VERSION 5.8 ;
BUSBITCHARS "[]" ;
DIVIDERCHAR "/" ;
UNITS
    DATABASE MICRONS 1000 ;
END UNITS

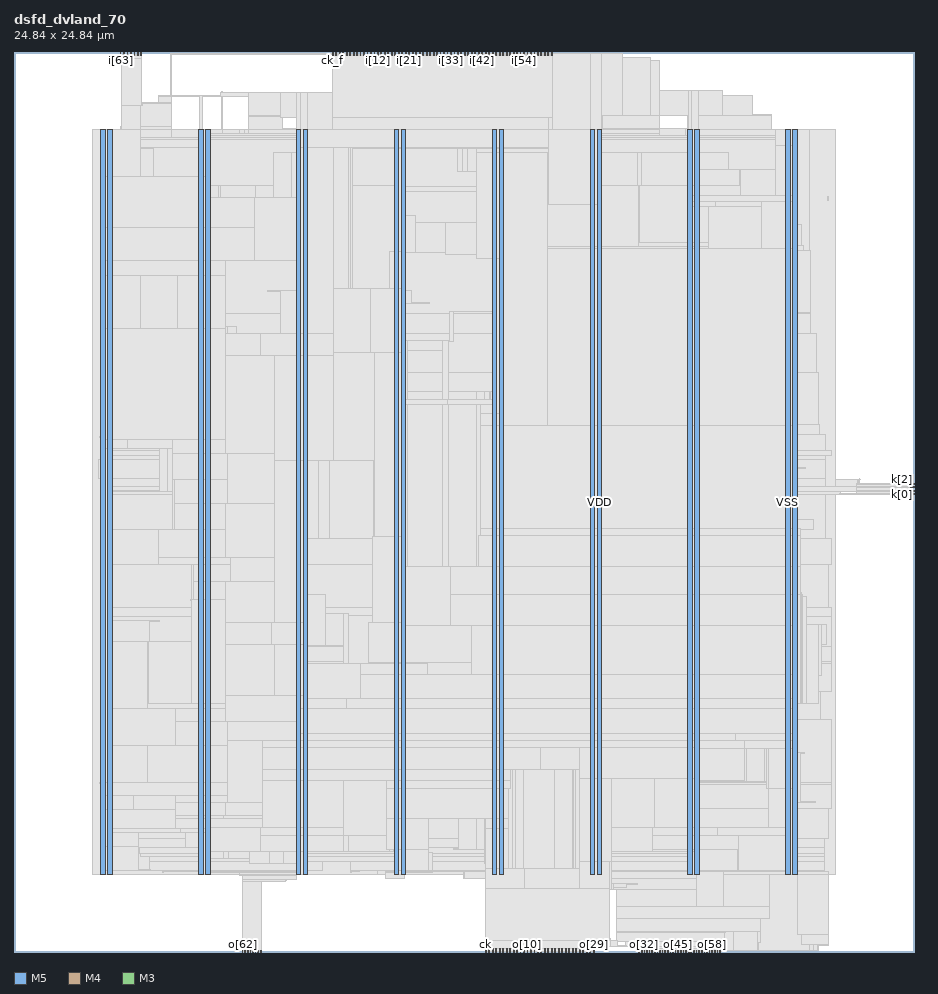
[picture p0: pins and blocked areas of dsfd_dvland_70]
MACRO dsfd_dvland_70
  FOREIGN dsfd_dvland_70 0 0 ;
  CLASS BLOCK ;
  SIZE 24.84 BY 24.84 ;
  PIN ck
    DIRECTION INPUT ;
    USE SIGNAL ;
    PORT
      LAYER M5 ;
        RECT  13.008 0 13.032 0.084 ;
    END
  END ck
  PIN ck_f
    DIRECTION INPUT ;
    USE SIGNAL ;
    PORT
      LAYER M5 ;
        RECT  8.784 24.756 8.808 24.84 ;
    END
  END ck_f
  PIN fault
    DIRECTION OUTPUT ;
    USE SIGNAL ;
    PORT
      LAYER M5 ;
        RECT  13.104 0 13.128 0.084 ;
    END
  END fault
  PIN i[0]
    DIRECTION INPUT ;
    USE SIGNAL ;
    PORT
      LAYER M5 ;
        RECT  8.88 24.756 8.904 24.84 ;
    END
  END i[0]
  PIN i[10]
    DIRECTION INPUT ;
    USE SIGNAL ;
    PORT
      LAYER M5 ;
        RECT  9.84 24.756 9.864 24.84 ;
    END
  END i[10]
  PIN i[11]
    DIRECTION INPUT ;
    USE SIGNAL ;
    PORT
      LAYER M5 ;
        RECT  9.936 24.756 9.96 24.84 ;
    END
  END i[11]
  PIN i[12]
    DIRECTION INPUT ;
    USE SIGNAL ;
    PORT
      LAYER M5 ;
        RECT  10.032 24.756 10.056 24.84 ;
    END
  END i[12]
  PIN i[13]
    DIRECTION INPUT ;
    USE SIGNAL ;
    PORT
      LAYER M5 ;
        RECT  10.128 24.756 10.152 24.84 ;
    END
  END i[13]
  PIN i[14]
    DIRECTION INPUT ;
    USE SIGNAL ;
    PORT
      LAYER M5 ;
        RECT  10.224 24.756 10.248 24.84 ;
    END
  END i[14]
  PIN i[15]
    DIRECTION INPUT ;
    USE SIGNAL ;
    PORT
      LAYER M5 ;
        RECT  10.32 24.756 10.344 24.84 ;
    END
  END i[15]
  PIN i[16]
    DIRECTION INPUT ;
    USE SIGNAL ;
    PORT
      LAYER M5 ;
        RECT  10.416 24.756 10.44 24.84 ;
    END
  END i[16]
  PIN i[17]
    DIRECTION INPUT ;
    USE SIGNAL ;
    PORT
      LAYER M5 ;
        RECT  10.512 24.756 10.536 24.84 ;
    END
  END i[17]
  PIN i[18]
    DIRECTION INPUT ;
    USE SIGNAL ;
    PORT
      LAYER M5 ;
        RECT  10.608 24.756 10.632 24.84 ;
    END
  END i[18]
  PIN i[19]
    DIRECTION INPUT ;
    USE SIGNAL ;
    PORT
      LAYER M5 ;
        RECT  10.704 24.756 10.728 24.84 ;
    END
  END i[19]
  PIN i[1]
    DIRECTION INPUT ;
    USE SIGNAL ;
    PORT
      LAYER M5 ;
        RECT  8.976 24.756 9 24.84 ;
    END
  END i[1]
  PIN i[20]
    DIRECTION INPUT ;
    USE SIGNAL ;
    PORT
      LAYER M5 ;
        RECT  10.8 24.756 10.824 24.84 ;
    END
  END i[20]
  PIN i[21]
    DIRECTION INPUT ;
    USE SIGNAL ;
    PORT
      LAYER M5 ;
        RECT  10.896 24.756 10.92 24.84 ;
    END
  END i[21]
  PIN i[22]
    DIRECTION INPUT ;
    USE SIGNAL ;
    PORT
      LAYER M5 ;
        RECT  10.992 24.756 11.016 24.84 ;
    END
  END i[22]
  PIN i[23]
    DIRECTION INPUT ;
    USE SIGNAL ;
    PORT
      LAYER M5 ;
        RECT  11.088 24.756 11.112 24.84 ;
    END
  END i[23]
  PIN i[24]
    DIRECTION INPUT ;
    USE SIGNAL ;
    PORT
      LAYER M5 ;
        RECT  11.184 24.756 11.208 24.84 ;
    END
  END i[24]
  PIN i[25]
    DIRECTION INPUT ;
    USE SIGNAL ;
    PORT
      LAYER M5 ;
        RECT  11.28 24.756 11.304 24.84 ;
    END
  END i[25]
  PIN i[26]
    DIRECTION INPUT ;
    USE SIGNAL ;
    PORT
      LAYER M5 ;
        RECT  11.376 24.756 11.4 24.84 ;
    END
  END i[26]
  PIN i[27]
    DIRECTION INPUT ;
    USE SIGNAL ;
    PORT
      LAYER M5 ;
        RECT  11.472 24.756 11.496 24.84 ;
    END
  END i[27]
  PIN i[28]
    DIRECTION INPUT ;
    USE SIGNAL ;
    PORT
      LAYER M5 ;
        RECT  11.568 24.756 11.592 24.84 ;
    END
  END i[28]
  PIN i[29]
    DIRECTION INPUT ;
    USE SIGNAL ;
    PORT
      LAYER M5 ;
        RECT  11.664 24.756 11.688 24.84 ;
    END
  END i[29]
  PIN i[2]
    DIRECTION INPUT ;
    USE SIGNAL ;
    PORT
      LAYER M5 ;
        RECT  9.072 24.756 9.096 24.84 ;
    END
  END i[2]
  PIN i[30]
    DIRECTION INPUT ;
    USE SIGNAL ;
    PORT
      LAYER M5 ;
        RECT  11.76 24.756 11.784 24.84 ;
    END
  END i[30]
  PIN i[31]
    DIRECTION INPUT ;
    USE SIGNAL ;
    PORT
      LAYER M5 ;
        RECT  11.856 24.756 11.88 24.84 ;
    END
  END i[31]
  PIN i[32]
    DIRECTION INPUT ;
    USE SIGNAL ;
    PORT
      LAYER M5 ;
        RECT  11.952 24.756 11.976 24.84 ;
    END
  END i[32]
  PIN i[33]
    DIRECTION INPUT ;
    USE SIGNAL ;
    PORT
      LAYER M5 ;
        RECT  12.048 24.756 12.072 24.84 ;
    END
  END i[33]
  PIN i[34]
    DIRECTION INPUT ;
    USE SIGNAL ;
    PORT
      LAYER M5 ;
        RECT  12.144 24.756 12.168 24.84 ;
    END
  END i[34]
  PIN i[35]
    DIRECTION INPUT ;
    USE SIGNAL ;
    PORT
      LAYER M5 ;
        RECT  12.24 24.756 12.264 24.84 ;
    END
  END i[35]
  PIN i[36]
    DIRECTION INPUT ;
    USE SIGNAL ;
    PORT
      LAYER M5 ;
        RECT  12.336 24.756 12.36 24.84 ;
    END
  END i[36]
  PIN i[37]
    DIRECTION INPUT ;
    USE SIGNAL ;
    PORT
      LAYER M5 ;
        RECT  12.432 24.756 12.456 24.84 ;
    END
  END i[37]
  PIN i[38]
    DIRECTION INPUT ;
    USE SIGNAL ;
    PORT
      LAYER M5 ;
        RECT  12.528 24.756 12.552 24.84 ;
    END
  END i[38]
  PIN i[39]
    DIRECTION INPUT ;
    USE SIGNAL ;
    PORT
      LAYER M5 ;
        RECT  12.624 24.756 12.648 24.84 ;
    END
  END i[39]
  PIN i[3]
    DIRECTION INPUT ;
    USE SIGNAL ;
    PORT
      LAYER M5 ;
        RECT  9.168 24.756 9.192 24.84 ;
    END
  END i[3]
  PIN i[40]
    DIRECTION INPUT ;
    USE SIGNAL ;
    PORT
      LAYER M5 ;
        RECT  12.72 24.756 12.744 24.84 ;
    END
  END i[40]
  PIN i[41]
    DIRECTION INPUT ;
    USE SIGNAL ;
    PORT
      LAYER M5 ;
        RECT  12.816 24.756 12.84 24.84 ;
    END
  END i[41]
  PIN i[42]
    DIRECTION INPUT ;
    USE SIGNAL ;
    PORT
      LAYER M5 ;
        RECT  12.912 24.756 12.936 24.84 ;
    END
  END i[42]
  PIN i[43]
    DIRECTION INPUT ;
    USE SIGNAL ;
    PORT
      LAYER M5 ;
        RECT  13.008 24.756 13.032 24.84 ;
    END
  END i[43]
  PIN i[44]
    DIRECTION INPUT ;
    USE SIGNAL ;
    PORT
      LAYER M5 ;
        RECT  13.104 24.756 13.128 24.84 ;
    END
  END i[44]
  PIN i[45]
    DIRECTION INPUT ;
    USE SIGNAL ;
    PORT
      LAYER M5 ;
        RECT  13.2 24.756 13.224 24.84 ;
    END
  END i[45]
  PIN i[46]
    DIRECTION INPUT ;
    USE SIGNAL ;
    PORT
      LAYER M5 ;
        RECT  13.296 24.756 13.32 24.84 ;
    END
  END i[46]
  PIN i[47]
    DIRECTION INPUT ;
    USE SIGNAL ;
    PORT
      LAYER M5 ;
        RECT  13.392 24.756 13.416 24.84 ;
    END
  END i[47]
  PIN i[48]
    DIRECTION INPUT ;
    USE SIGNAL ;
    PORT
      LAYER M5 ;
        RECT  13.488 24.756 13.512 24.84 ;
    END
  END i[48]
  PIN i[49]
    DIRECTION INPUT ;
    USE SIGNAL ;
    PORT
      LAYER M5 ;
        RECT  13.584 24.756 13.608 24.84 ;
    END
  END i[49]
  PIN i[4]
    DIRECTION INPUT ;
    USE SIGNAL ;
    PORT
      LAYER M5 ;
        RECT  9.264 24.756 9.288 24.84 ;
    END
  END i[4]
  PIN i[50]
    DIRECTION INPUT ;
    USE SIGNAL ;
    PORT
      LAYER M5 ;
        RECT  13.68 24.756 13.704 24.84 ;
    END
  END i[50]
  PIN i[51]
    DIRECTION INPUT ;
    USE SIGNAL ;
    PORT
      LAYER M5 ;
        RECT  13.776 24.756 13.8 24.84 ;
    END
  END i[51]
  PIN i[52]
    DIRECTION INPUT ;
    USE SIGNAL ;
    PORT
      LAYER M5 ;
        RECT  13.872 24.756 13.896 24.84 ;
    END
  END i[52]
  PIN i[53]
    DIRECTION INPUT ;
    USE SIGNAL ;
    PORT
      LAYER M5 ;
        RECT  13.968 24.756 13.992 24.84 ;
    END
  END i[53]
  PIN i[54]
    DIRECTION INPUT ;
    USE SIGNAL ;
    PORT
      LAYER M5 ;
        RECT  14.064 24.756 14.088 24.84 ;
    END
  END i[54]
  PIN i[55]
    DIRECTION INPUT ;
    USE SIGNAL ;
    PORT
      LAYER M5 ;
        RECT  14.16 24.756 14.184 24.84 ;
    END
  END i[55]
  PIN i[56]
    DIRECTION INPUT ;
    USE SIGNAL ;
    PORT
      LAYER M5 ;
        RECT  14.256 24.756 14.28 24.84 ;
    END
  END i[56]
  PIN i[57]
    DIRECTION INPUT ;
    USE SIGNAL ;
    PORT
      LAYER M5 ;
        RECT  14.352 24.756 14.376 24.84 ;
    END
  END i[57]
  PIN i[58]
    DIRECTION INPUT ;
    USE SIGNAL ;
    PORT
      LAYER M5 ;
        RECT  14.448 24.756 14.472 24.84 ;
    END
  END i[58]
  PIN i[59]
    DIRECTION INPUT ;
    USE SIGNAL ;
    PORT
      LAYER M5 ;
        RECT  14.544 24.756 14.568 24.84 ;
    END
  END i[59]
  PIN i[5]
    DIRECTION INPUT ;
    USE SIGNAL ;
    PORT
      LAYER M5 ;
        RECT  9.36 24.756 9.384 24.84 ;
    END
  END i[5]
  PIN i[60]
    DIRECTION INPUT ;
    USE SIGNAL ;
    PORT
      LAYER M5 ;
        RECT  14.64 24.756 14.664 24.84 ;
    END
  END i[60]
  PIN i[61]
    DIRECTION INPUT ;
    USE SIGNAL ;
    PORT
      LAYER M5 ;
        RECT  14.736 24.756 14.76 24.84 ;
    END
  END i[61]
  PIN i[62]
    DIRECTION INPUT ;
    USE SIGNAL ;
    PORT
      LAYER M5 ;
        RECT  14.832 24.756 14.856 24.84 ;
    END
  END i[62]
  PIN i[63]
    DIRECTION INPUT ;
    USE SIGNAL ;
    PORT
      LAYER M5 ;
        RECT  2.928 24.756 2.952 24.84 ;
    END
  END i[63]
  PIN i[64]
    DIRECTION INPUT ;
    USE SIGNAL ;
    PORT
      LAYER M5 ;
        RECT  3.024 24.756 3.048 24.84 ;
    END
  END i[64]
  PIN i[65]
    DIRECTION INPUT ;
    USE SIGNAL ;
    PORT
      LAYER M5 ;
        RECT  3.12 24.756 3.144 24.84 ;
    END
  END i[65]
  PIN i[66]
    DIRECTION INPUT ;
    USE SIGNAL ;
    PORT
      LAYER M5 ;
        RECT  3.216 24.756 3.24 24.84 ;
    END
  END i[66]
  PIN i[67]
    DIRECTION INPUT ;
    USE SIGNAL ;
    PORT
      LAYER M5 ;
        RECT  3.312 24.756 3.336 24.84 ;
    END
  END i[67]
  PIN i[68]
    DIRECTION INPUT ;
    USE SIGNAL ;
    PORT
      LAYER M5 ;
        RECT  3.408 24.756 3.432 24.84 ;
    END
  END i[68]
  PIN i[69]
    DIRECTION INPUT ;
    USE SIGNAL ;
    PORT
      LAYER M5 ;
        RECT  3.504 24.756 3.528 24.84 ;
    END
  END i[69]
  PIN i[6]
    DIRECTION INPUT ;
    USE SIGNAL ;
    PORT
      LAYER M5 ;
        RECT  9.456 24.756 9.48 24.84 ;
    END
  END i[6]
  PIN i[7]
    DIRECTION INPUT ;
    USE SIGNAL ;
    PORT
      LAYER M5 ;
        RECT  9.552 24.756 9.576 24.84 ;
    END
  END i[7]
  PIN i[8]
    DIRECTION INPUT ;
    USE SIGNAL ;
    PORT
      LAYER M5 ;
        RECT  9.648 24.756 9.672 24.84 ;
    END
  END i[8]
  PIN i[9]
    DIRECTION INPUT ;
    USE SIGNAL ;
    PORT
      LAYER M5 ;
        RECT  9.744 24.756 9.768 24.84 ;
    END
  END i[9]
  PIN k[0]
    DIRECTION INPUT ;
    USE SIGNAL ;
    PORT
      LAYER M4 ;
        RECT  24.756 12.624 24.84 12.648 ;
    END
  END k[0]
  PIN k[1]
    DIRECTION INPUT ;
    USE SIGNAL ;
    PORT
      LAYER M4 ;
        RECT  24.756 12.72 24.84 12.744 ;
    END
  END k[1]
  PIN k[2]
    DIRECTION INPUT ;
    USE SIGNAL ;
    PORT
      LAYER M4 ;
        RECT  24.756 12.816 24.84 12.84 ;
    END
  END k[2]
  PIN o[0]
    DIRECTION OUTPUT ;
    USE SIGNAL ;
    PORT
      LAYER M5 ;
        RECT  13.2 0 13.224 0.084 ;
    END
  END o[0]
  PIN o[10]
    DIRECTION OUTPUT ;
    USE SIGNAL ;
    PORT
      LAYER M5 ;
        RECT  14.16 0 14.184 0.084 ;
    END
  END o[10]
  PIN o[11]
    DIRECTION OUTPUT ;
    USE SIGNAL ;
    PORT
      LAYER M5 ;
        RECT  14.256 0 14.28 0.084 ;
    END
  END o[11]
  PIN o[12]
    DIRECTION OUTPUT ;
    USE SIGNAL ;
    PORT
      LAYER M5 ;
        RECT  14.352 0 14.376 0.084 ;
    END
  END o[12]
  PIN o[13]
    DIRECTION OUTPUT ;
    USE SIGNAL ;
    PORT
      LAYER M5 ;
        RECT  14.448 0 14.472 0.084 ;
    END
  END o[13]
  PIN o[14]
    DIRECTION OUTPUT ;
    USE SIGNAL ;
    PORT
      LAYER M5 ;
        RECT  14.544 0 14.568 0.084 ;
    END
  END o[14]
  PIN o[15]
    DIRECTION OUTPUT ;
    USE SIGNAL ;
    PORT
      LAYER M5 ;
        RECT  14.64 0 14.664 0.084 ;
    END
  END o[15]
  PIN o[16]
    DIRECTION OUTPUT ;
    USE SIGNAL ;
    PORT
      LAYER M5 ;
        RECT  14.736 0 14.76 0.084 ;
    END
  END o[16]
  PIN o[17]
    DIRECTION OUTPUT ;
    USE SIGNAL ;
    PORT
      LAYER M5 ;
        RECT  14.832 0 14.856 0.084 ;
    END
  END o[17]
  PIN o[18]
    DIRECTION OUTPUT ;
    USE SIGNAL ;
    PORT
      LAYER M5 ;
        RECT  14.928 0 14.952 0.084 ;
    END
  END o[18]
  PIN o[19]
    DIRECTION OUTPUT ;
    USE SIGNAL ;
    PORT
      LAYER M5 ;
        RECT  15.024 0 15.048 0.084 ;
    END
  END o[19]
  PIN o[1]
    DIRECTION OUTPUT ;
    USE SIGNAL ;
    PORT
      LAYER M5 ;
        RECT  13.296 0 13.32 0.084 ;
    END
  END o[1]
  PIN o[20]
    DIRECTION OUTPUT ;
    USE SIGNAL ;
    PORT
      LAYER M5 ;
        RECT  15.12 0 15.144 0.084 ;
    END
  END o[20]
  PIN o[21]
    DIRECTION OUTPUT ;
    USE SIGNAL ;
    PORT
      LAYER M5 ;
        RECT  15.216 0 15.24 0.084 ;
    END
  END o[21]
  PIN o[22]
    DIRECTION OUTPUT ;
    USE SIGNAL ;
    PORT
      LAYER M5 ;
        RECT  15.312 0 15.336 0.084 ;
    END
  END o[22]
  PIN o[23]
    DIRECTION OUTPUT ;
    USE SIGNAL ;
    PORT
      LAYER M5 ;
        RECT  15.408 0 15.432 0.084 ;
    END
  END o[23]
  PIN o[24]
    DIRECTION OUTPUT ;
    USE SIGNAL ;
    PORT
      LAYER M5 ;
        RECT  15.504 0 15.528 0.084 ;
    END
  END o[24]
  PIN o[25]
    DIRECTION OUTPUT ;
    USE SIGNAL ;
    PORT
      LAYER M5 ;
        RECT  15.6 0 15.624 0.084 ;
    END
  END o[25]
  PIN o[26]
    DIRECTION OUTPUT ;
    USE SIGNAL ;
    PORT
      LAYER M5 ;
        RECT  15.696 0 15.72 0.084 ;
    END
  END o[26]
  PIN o[27]
    DIRECTION OUTPUT ;
    USE SIGNAL ;
    PORT
      LAYER M5 ;
        RECT  15.792 0 15.816 0.084 ;
    END
  END o[27]
  PIN o[28]
    DIRECTION OUTPUT ;
    USE SIGNAL ;
    PORT
      LAYER M5 ;
        RECT  15.888 0 15.912 0.084 ;
    END
  END o[28]
  PIN o[29]
    DIRECTION OUTPUT ;
    USE SIGNAL ;
    PORT
      LAYER M5 ;
        RECT  15.984 0 16.008 0.084 ;
    END
  END o[29]
  PIN o[2]
    DIRECTION OUTPUT ;
    USE SIGNAL ;
    PORT
      LAYER M5 ;
        RECT  13.392 0 13.416 0.084 ;
    END
  END o[2]
  PIN o[30]
    DIRECTION OUTPUT ;
    USE SIGNAL ;
    PORT
      LAYER M3 ;
        RECT  17.244 0 17.262 0.037 ;
    END
  END o[30]
  PIN o[31]
    DIRECTION OUTPUT ;
    USE SIGNAL ;
    PORT
      LAYER M3 ;
        RECT  17.316 0 17.334 0.037 ;
    END
  END o[31]
  PIN o[32]
    DIRECTION OUTPUT ;
    USE SIGNAL ;
    PORT
      LAYER M3 ;
        RECT  17.388 0 17.406 0.037 ;
    END
  END o[32]
  PIN o[33]
    DIRECTION OUTPUT ;
    USE SIGNAL ;
    PORT
      LAYER M3 ;
        RECT  17.46 0 17.478 0.037 ;
    END
  END o[33]
  PIN o[34]
    DIRECTION OUTPUT ;
    USE SIGNAL ;
    PORT
      LAYER M3 ;
        RECT  17.532 0 17.55 0.037 ;
    END
  END o[34]
  PIN o[35]
    DIRECTION OUTPUT ;
    USE SIGNAL ;
    PORT
      LAYER M3 ;
        RECT  17.604 0 17.622 0.037 ;
    END
  END o[35]
  PIN o[36]
    DIRECTION OUTPUT ;
    USE SIGNAL ;
    PORT
      LAYER M3 ;
        RECT  17.676 0 17.694 0.037 ;
    END
  END o[36]
  PIN o[37]
    DIRECTION OUTPUT ;
    USE SIGNAL ;
    PORT
      LAYER M3 ;
        RECT  17.748 0 17.766 0.037 ;
    END
  END o[37]
  PIN o[38]
    DIRECTION OUTPUT ;
    USE SIGNAL ;
    PORT
      LAYER M3 ;
        RECT  17.82 0 17.838 0.037 ;
    END
  END o[38]
  PIN o[39]
    DIRECTION OUTPUT ;
    USE SIGNAL ;
    PORT
      LAYER M3 ;
        RECT  17.892 0 17.91 0.037 ;
    END
  END o[39]
  PIN o[3]
    DIRECTION OUTPUT ;
    USE SIGNAL ;
    PORT
      LAYER M5 ;
        RECT  13.488 0 13.512 0.084 ;
    END
  END o[3]
  PIN o[40]
    DIRECTION OUTPUT ;
    USE SIGNAL ;
    PORT
      LAYER M3 ;
        RECT  17.964 0 17.982 0.037 ;
    END
  END o[40]
  PIN o[41]
    DIRECTION OUTPUT ;
    USE SIGNAL ;
    PORT
      LAYER M3 ;
        RECT  18.036 0 18.054 0.037 ;
    END
  END o[41]
  PIN o[42]
    DIRECTION OUTPUT ;
    USE SIGNAL ;
    PORT
      LAYER M3 ;
        RECT  18.108 0 18.126 0.037 ;
    END
  END o[42]
  PIN o[43]
    DIRECTION OUTPUT ;
    USE SIGNAL ;
    PORT
      LAYER M3 ;
        RECT  18.18 0 18.198 0.037 ;
    END
  END o[43]
  PIN o[44]
    DIRECTION OUTPUT ;
    USE SIGNAL ;
    PORT
      LAYER M3 ;
        RECT  18.252 0 18.27 0.037 ;
    END
  END o[44]
  PIN o[45]
    DIRECTION OUTPUT ;
    USE SIGNAL ;
    PORT
      LAYER M3 ;
        RECT  18.324 0 18.342 0.037 ;
    END
  END o[45]
  PIN o[46]
    DIRECTION OUTPUT ;
    USE SIGNAL ;
    PORT
      LAYER M3 ;
        RECT  18.396 0 18.414 0.037 ;
    END
  END o[46]
  PIN o[47]
    DIRECTION OUTPUT ;
    USE SIGNAL ;
    PORT
      LAYER M3 ;
        RECT  18.468 0 18.486 0.037 ;
    END
  END o[47]
  PIN o[48]
    DIRECTION OUTPUT ;
    USE SIGNAL ;
    PORT
      LAYER M3 ;
        RECT  18.54 0 18.558 0.037 ;
    END
  END o[48]
  PIN o[49]
    DIRECTION OUTPUT ;
    USE SIGNAL ;
    PORT
      LAYER M3 ;
        RECT  18.612 0 18.63 0.037 ;
    END
  END o[49]
  PIN o[4]
    DIRECTION OUTPUT ;
    USE SIGNAL ;
    PORT
      LAYER M5 ;
        RECT  13.584 0 13.608 0.084 ;
    END
  END o[4]
  PIN o[50]
    DIRECTION OUTPUT ;
    USE SIGNAL ;
    PORT
      LAYER M3 ;
        RECT  18.684 0 18.702 0.037 ;
    END
  END o[50]
  PIN o[51]
    DIRECTION OUTPUT ;
    USE SIGNAL ;
    PORT
      LAYER M3 ;
        RECT  18.756 0 18.774 0.037 ;
    END
  END o[51]
  PIN o[52]
    DIRECTION OUTPUT ;
    USE SIGNAL ;
    PORT
      LAYER M3 ;
        RECT  18.828 0 18.846 0.037 ;
    END
  END o[52]
  PIN o[53]
    DIRECTION OUTPUT ;
    USE SIGNAL ;
    PORT
      LAYER M3 ;
        RECT  18.9 0 18.918 0.037 ;
    END
  END o[53]
  PIN o[54]
    DIRECTION OUTPUT ;
    USE SIGNAL ;
    PORT
      LAYER M3 ;
        RECT  18.972 0 18.99 0.037 ;
    END
  END o[54]
  PIN o[55]
    DIRECTION OUTPUT ;
    USE SIGNAL ;
    PORT
      LAYER M3 ;
        RECT  19.044 0 19.062 0.037 ;
    END
  END o[55]
  PIN o[56]
    DIRECTION OUTPUT ;
    USE SIGNAL ;
    PORT
      LAYER M3 ;
        RECT  19.116 0 19.134 0.037 ;
    END
  END o[56]
  PIN o[57]
    DIRECTION OUTPUT ;
    USE SIGNAL ;
    PORT
      LAYER M3 ;
        RECT  19.188 0 19.206 0.037 ;
    END
  END o[57]
  PIN o[58]
    DIRECTION OUTPUT ;
    USE SIGNAL ;
    PORT
      LAYER M3 ;
        RECT  19.26 0 19.278 0.037 ;
    END
  END o[58]
  PIN o[59]
    DIRECTION OUTPUT ;
    USE SIGNAL ;
    PORT
      LAYER M3 ;
        RECT  19.332 0 19.35 0.037 ;
    END
  END o[59]
  PIN o[5]
    DIRECTION OUTPUT ;
    USE SIGNAL ;
    PORT
      LAYER M5 ;
        RECT  13.68 0 13.704 0.084 ;
    END
  END o[5]
  PIN o[60]
    DIRECTION OUTPUT ;
    USE SIGNAL ;
    PORT
      LAYER M3 ;
        RECT  19.404 0 19.422 0.037 ;
    END
  END o[60]
  PIN o[61]
    DIRECTION OUTPUT ;
    USE SIGNAL ;
    PORT
      LAYER M3 ;
        RECT  19.476 0 19.494 0.037 ;
    END
  END o[61]
  PIN o[62]
    DIRECTION OUTPUT ;
    USE SIGNAL ;
    PORT
      LAYER M3 ;
        RECT  6.3 0 6.318 0.037 ;
    END
  END o[62]
  PIN o[63]
    DIRECTION OUTPUT ;
    USE SIGNAL ;
    PORT
      LAYER M3 ;
        RECT  6.372 0 6.39 0.037 ;
    END
  END o[63]
  PIN o[64]
    DIRECTION OUTPUT ;
    USE SIGNAL ;
    PORT
      LAYER M3 ;
        RECT  6.444 0 6.462 0.037 ;
    END
  END o[64]
  PIN o[65]
    DIRECTION OUTPUT ;
    USE SIGNAL ;
    PORT
      LAYER M3 ;
        RECT  6.516 0 6.534 0.037 ;
    END
  END o[65]
  PIN o[66]
    DIRECTION OUTPUT ;
    USE SIGNAL ;
    PORT
      LAYER M3 ;
        RECT  6.588 0 6.606 0.037 ;
    END
  END o[66]
  PIN o[67]
    DIRECTION OUTPUT ;
    USE SIGNAL ;
    PORT
      LAYER M3 ;
        RECT  6.66 0 6.678 0.037 ;
    END
  END o[67]
  PIN o[68]
    DIRECTION OUTPUT ;
    USE SIGNAL ;
    PORT
      LAYER M3 ;
        RECT  6.732 0 6.75 0.037 ;
    END
  END o[68]
  PIN o[69]
    DIRECTION OUTPUT ;
    USE SIGNAL ;
    PORT
      LAYER M3 ;
        RECT  6.804 0 6.822 0.037 ;
    END
  END o[69]
  PIN o[6]
    DIRECTION OUTPUT ;
    USE SIGNAL ;
    PORT
      LAYER M5 ;
        RECT  13.776 0 13.8 0.084 ;
    END
  END o[6]
  PIN o[7]
    DIRECTION OUTPUT ;
    USE SIGNAL ;
    PORT
      LAYER M5 ;
        RECT  13.872 0 13.896 0.084 ;
    END
  END o[7]
  PIN o[8]
    DIRECTION OUTPUT ;
    USE SIGNAL ;
    PORT
      LAYER M5 ;
        RECT  13.968 0 13.992 0.084 ;
    END
  END o[8]
  PIN o[9]
    DIRECTION OUTPUT ;
    USE SIGNAL ;
    PORT
      LAYER M5 ;
        RECT  14.064 0 14.088 0.084 ;
    END
  END o[9]
  PIN rs
    DIRECTION INPUT ;
    USE SIGNAL ;
    PORT
      LAYER M4 ;
        RECT  24.756 12.912 24.84 12.936 ;
    END
  END rs
  PIN VDD
    DIRECTION INOUT ;
    USE POWER ;
    PORT
      LAYER M5 ;
        RECT  21.492 2.151 21.612 22.689 ;
        RECT  18.792 2.151 18.912 22.689 ;
        RECT  16.092 2.151 16.212 22.689 ;
        RECT  13.392 2.151 13.512 22.689 ;
        RECT  10.692 2.151 10.812 22.689 ;
        RECT  7.992 2.151 8.112 22.689 ;
        RECT  5.292 2.151 5.412 22.689 ;
        RECT  2.592 2.151 2.712 22.689 ;
    END
  END VDD
  PIN VSS
    DIRECTION INOUT ;
    USE GROUND ;
    PORT
      LAYER M5 ;
        RECT  21.3 2.137 21.42 22.703 ;
        RECT  18.6 2.137 18.72 22.703 ;
        RECT  15.9 2.137 16.02 22.703 ;
        RECT  13.2 2.137 13.32 22.703 ;
        RECT  10.5 2.137 10.62 22.703 ;
        RECT  7.8 2.137 7.92 22.703 ;
        RECT  5.1 2.137 5.22 22.703 ;
        RECT  2.4 2.137 2.52 22.703 ;
    END
  END VSS
  # OT_OBS_CLOSED layer=M5 d_um=1.536 added=62
  OBS
    LAYER RVTN ;
     RECT  2.16 2.16 22.68 2.295 ;
     RECT  2.16 2.565 22.68 2.835 ;
     RECT  2.16 3.105 22.68 3.375 ;
     RECT  2.16 3.645 22.68 3.915 ;
     RECT  2.16 4.185 22.68 4.455 ;
     RECT  2.16 4.725 22.68 4.995 ;
     RECT  2.16 5.265 22.68 5.535 ;
     RECT  2.16 5.805 22.68 6.075 ;
     RECT  2.16 6.345 22.68 6.615 ;
     RECT  2.16 6.885 22.68 7.155 ;
     RECT  2.16 7.425 22.68 7.695 ;
     RECT  2.16 7.965 22.68 8.235 ;
     RECT  2.16 8.505 22.68 8.775 ;
     RECT  2.16 9.045 22.68 9.315 ;
     RECT  2.16 9.585 22.68 9.855 ;
     RECT  2.16 10.125 22.68 10.395 ;
     RECT  2.16 10.665 22.68 10.935 ;
     RECT  2.16 11.205 22.68 11.475 ;
     RECT  2.16 11.745 22.68 12.015 ;
     RECT  2.16 12.285 22.68 12.555 ;
     RECT  2.16 12.825 22.68 13.095 ;
     RECT  2.16 13.365 22.68 13.635 ;
     RECT  2.16 13.905 22.68 14.175 ;
     RECT  2.16 14.445 22.68 14.715 ;
     RECT  2.16 14.985 22.68 15.255 ;
     RECT  2.16 15.525 22.68 15.795 ;
     RECT  2.16 16.065 22.68 16.335 ;
     RECT  2.16 16.605 22.68 16.875 ;
     RECT  2.16 17.145 22.68 17.415 ;
     RECT  2.16 17.685 22.68 17.955 ;
     RECT  2.16 18.225 22.68 18.495 ;
     RECT  2.16 18.765 22.68 19.035 ;
     RECT  2.16 19.305 22.68 19.575 ;
     RECT  2.16 19.845 22.68 20.115 ;
     RECT  2.16 20.385 22.68 20.655 ;
     RECT  2.16 20.925 22.68 21.195 ;
     RECT  2.16 21.465 22.68 21.735 ;
     RECT  2.16 22.005 22.68 22.275 ;
     RECT  2.16 22.545 22.68 22.68 ;
    LAYER RVTP ;
     RECT  2.16 2.295 22.68 2.565 ;
     RECT  2.16 2.835 22.68 3.105 ;
     RECT  2.16 3.375 22.68 3.645 ;
     RECT  2.16 3.915 22.68 4.185 ;
     RECT  2.16 4.455 22.68 4.725 ;
     RECT  2.16 4.995 22.68 5.265 ;
     RECT  2.16 5.535 22.68 5.805 ;
     RECT  2.16 6.075 22.68 6.345 ;
     RECT  2.16 6.615 22.68 6.885 ;
     RECT  2.16 7.155 22.68 7.425 ;
     RECT  2.16 7.695 22.68 7.965 ;
     RECT  2.16 8.235 22.68 8.505 ;
     RECT  2.16 8.775 22.68 9.045 ;
     RECT  2.16 9.315 22.68 9.585 ;
     RECT  2.16 9.855 22.68 10.125 ;
     RECT  2.16 10.395 22.68 10.665 ;
     RECT  2.16 10.935 22.68 11.205 ;
     RECT  2.16 11.475 22.68 11.745 ;
     RECT  2.16 12.015 22.68 12.285 ;
     RECT  2.16 12.555 22.68 12.825 ;
     RECT  2.16 13.095 22.68 13.365 ;
     RECT  2.16 13.635 22.68 13.905 ;
     RECT  2.16 14.175 22.68 14.445 ;
     RECT  2.16 14.715 22.68 14.985 ;
     RECT  2.16 15.255 22.68 15.525 ;
     RECT  2.16 15.795 22.68 16.065 ;
     RECT  2.16 16.335 22.68 16.605 ;
     RECT  2.16 16.875 22.68 17.145 ;
     RECT  2.16 17.415 22.68 17.685 ;
     RECT  2.16 17.955 22.68 18.225 ;
     RECT  2.16 18.495 22.68 18.765 ;
     RECT  2.16 19.035 22.68 19.305 ;
     RECT  2.16 19.575 22.68 19.845 ;
     RECT  2.16 20.115 22.68 20.385 ;
     RECT  2.16 20.655 22.68 20.925 ;
     RECT  2.16 21.195 22.68 21.465 ;
     RECT  2.16 21.735 22.68 22.005 ;
     RECT  2.16 22.275 22.68 22.545 ;
    LAYER M1 ;
     RECT  2.16 2.151 22.68 22.689 ;
    LAYER M2 ;
     RECT  2.16 2.151 6.223 22.689 ;
     RECT  6.223 2.106 6.367 22.689 ;
     RECT  6.367 1.728 6.719 22.689 ;
     RECT  6.719 1.8 6.791 22.689 ;
     RECT  6.791 1.962 6.799 22.689 ;
     RECT  6.799 1.962 7.511 22.734 ;
     RECT  7.511 1.998 7.799 22.734 ;
     RECT  7.799 2.151 10.039 22.734 ;
     RECT  10.039 2.151 10.255 22.806 ;
     RECT  10.255 2.034 10.643 22.806 ;
     RECT  10.643 2.034 10.787 22.689 ;
     RECT  10.787 2.151 12.415 22.689 ;
     RECT  12.415 2.034 13.099 22.689 ;
     RECT  13.099 2.034 13.171 22.734 ;
     RECT  13.171 2.034 13.667 22.806 ;
     RECT  13.351 1.152 14.171 1.17 ;
     RECT  14.899 1.152 15.187 1.17 ;
     RECT  15.187 1.152 15.323 1.242 ;
     RECT  15.323 1.224 15.359 1.242 ;
     RECT  13.667 2.034 15.619 22.689 ;
     RECT  15.619 2.034 16.727 22.734 ;
     RECT  16.627 1.224 16.735 1.242 ;
     RECT  16.735 1.152 16.871 1.242 ;
     RECT  16.871 1.152 16.907 1.17 ;
     RECT  17.311 0.108 17.383 0.126 ;
     RECT  17.383 0.036 17.815 0.126 ;
     RECT  17.815 0.036 18.031 0.162 ;
     RECT  17.923 1.152 18.103 1.359 ;
     RECT  18.031 0.036 18.319 0.198 ;
     RECT  18.103 0.954 18.319 1.359 ;
     RECT  16.727 2.151 18.535 22.734 ;
     RECT  18.319 0.036 18.751 1.359 ;
     RECT  18.535 2.106 18.751 22.734 ;
     RECT  18.751 0.036 19.859 22.734 ;
     RECT  19.859 0.036 21.947 22.689 ;
     RECT  21.947 0.036 22.055 1.17 ;
     RECT  22.055 0.036 22.199 0.864 ;
     RECT  22.199 0.18 22.379 0.864 ;
     RECT  22.379 0.18 22.487 0.198 ;
     RECT  21.947 2.151 22.68 22.689 ;
     RECT  22.68 12.726 23.279 13.05 ;
     RECT  23.279 12.798 23.315 13.05 ;
     RECT  23.315 13.032 23.351 13.05 ;
    LAYER M3 ;
     RECT  17.262 0.012 17.316 0.037 ;
     RECT  17.334 0.012 17.388 0.037 ;
     RECT  17.406 0.012 17.46 0.037 ;
     RECT  17.478 0.012 17.532 0.037 ;
     RECT  17.55 0.012 17.604 0.037 ;
     RECT  17.622 0.012 17.676 0.037 ;
     RECT  17.694 0.012 17.748 0.037 ;
     RECT  17.766 0.012 17.82 0.037 ;
     RECT  17.838 0.012 17.892 0.037 ;
     RECT  17.91 0.012 17.964 0.037 ;
     RECT  17.982 0.012 18.036 0.037 ;
     RECT  18.054 0.012 18.108 0.037 ;
     RECT  18.126 0.012 18.18 0.037 ;
     RECT  18.198 0.012 18.252 0.037 ;
     RECT  18.27 0.012 18.324 0.037 ;
     RECT  18.342 0.012 18.396 0.037 ;
     RECT  18.414 0.012 18.468 0.037 ;
     RECT  18.486 0.012 18.54 0.037 ;
     RECT  18.558 0.012 18.612 0.037 ;
     RECT  18.63 0.012 18.684 0.037 ;
     RECT  18.702 0.012 18.756 0.037 ;
     RECT  18.774 0.012 18.828 0.037 ;
     RECT  18.846 0.012 18.9 0.037 ;
     RECT  18.918 0.012 18.972 0.037 ;
     RECT  18.99 0.012 19.044 0.037 ;
     RECT  19.062 0.012 19.116 0.037 ;
     RECT  19.134 0.012 19.188 0.037 ;
     RECT  19.206 0.012 19.26 0.037 ;
     RECT  19.278 0.012 19.332 0.037 ;
     RECT  19.35 0.012 19.404 0.037 ;
     RECT  19.422 0.012 19.476 0.037 ;
     RECT  17.244 0.037 19.494 0.103 ;
     RECT  13.572 0.091 13.95 0.139 ;
     RECT  15.084 0.091 15.966 0.139 ;
     RECT  17.244 0.103 19.602 0.139 ;
     RECT  22.176 0.031 22.194 0.175 ;
     RECT  22.176 0.175 22.482 0.211 ;
     RECT  14.832 0.139 15.966 0.221 ;
     RECT  13.572 0.139 14.094 0.235 ;
     RECT  14.832 0.221 15.858 0.235 ;
     RECT  20.52 0.067 20.538 0.256 ;
     RECT  16.884 0.139 19.602 0.283 ;
     RECT  21.744 0.211 22.482 0.481 ;
     RECT  16.632 0.283 19.602 0.526 ;
     RECT  13.572 0.235 15.858 0.571 ;
     RECT  16.632 0.526 19.638 0.571 ;
     RECT  20.52 0.256 20.61 0.571 ;
     RECT  16.632 0.571 20.61 0.913 ;
     RECT  13.176 0.571 15.858 1.147 ;
     RECT  16.632 0.913 20.862 1.247 ;
     RECT  13.104 1.147 15.858 1.723 ;
     RECT  16.632 1.247 18.846 1.723 ;
     RECT  6.318 0.012 6.372 0.037 ;
     RECT  6.39 0.012 6.444 0.037 ;
     RECT  6.462 0.012 6.516 0.037 ;
     RECT  6.534 0.012 6.588 0.037 ;
     RECT  6.606 0.012 6.66 0.037 ;
     RECT  6.678 0.012 6.732 0.037 ;
     RECT  6.75 0.012 6.804 0.037 ;
     RECT  6.3 0.037 6.822 1.957 ;
     RECT  6.3 1.957 7.506 1.993 ;
     RECT  13.104 1.723 18.846 2.029 ;
     RECT  6.3 1.993 7.794 2.101 ;
     RECT  6.228 2.101 7.794 2.143 ;
     RECT  19.584 1.247 20.862 2.143 ;
     RECT  21.636 0.481 22.482 2.143 ;
     RECT  5.115 2.143 5.205 2.191 ;
     RECT  6.228 2.143 7.905 2.191 ;
     RECT  10.26 2.029 10.782 2.191 ;
     RECT  19.584 2.143 22.482 2.219 ;
     RECT  4.104 2.191 4.122 2.227 ;
     RECT  5.115 2.191 7.905 2.227 ;
     RECT  9.288 2.191 9.306 2.227 ;
     RECT  10.26 2.191 11.538 2.227 ;
     RECT  12.42 2.029 18.846 2.227 ;
     RECT  19.584 2.219 22.374 2.227 ;
     RECT  4.104 2.227 7.905 2.251 ;
     RECT  3.744 2.251 7.905 2.263 ;
     RECT  9.288 2.227 9.522 2.263 ;
     RECT  10.26 2.227 22.374 2.263 ;
     RECT  2.415 2.143 2.505 2.413 ;
     RECT  3.744 2.263 8.514 2.497 ;
     RECT  9.288 2.263 22.374 2.497 ;
     RECT  3.744 2.497 22.374 2.641 ;
     RECT  3.492 2.641 22.374 2.731 ;
     RECT  2.415 2.413 2.697 2.875 ;
     RECT  3.456 2.731 22.374 2.875 ;
     RECT  2.415 2.875 22.374 3.145 ;
     RECT  2.415 3.145 22.482 3.955 ;
     RECT  2.415 3.955 22.554 4.621 ;
     RECT  2.376 4.621 22.554 4.685 ;
     RECT  2.415 4.685 22.554 6.413 ;
     RECT  2.415 6.413 22.266 7.195 ;
     RECT  2.415 7.195 22.554 7.963 ;
     RECT  2.412 7.963 22.554 8.005 ;
     RECT  2.376 8.005 22.554 8.429 ;
     RECT  2.415 8.429 22.554 9.247 ;
     RECT  2.376 9.247 22.554 9.509 ;
     RECT  2.415 9.509 22.482 10.705 ;
     RECT  2.415 10.705 22.554 11.399 ;
     RECT  2.415 11.399 22.41 12.619 ;
     RECT  2.415 12.619 22.806 12.715 ;
     RECT  2.415 12.715 23.346 12.857 ;
     RECT  23.256 12.857 23.346 12.941 ;
     RECT  23.328 12.941 23.346 13.055 ;
     RECT  2.415 12.857 22.41 13.063 ;
     RECT  2.34 13.063 22.41 13.595 ;
     RECT  2.376 13.595 22.41 13.711 ;
     RECT  2.376 13.711 22.554 13.829 ;
     RECT  2.376 13.829 22.41 14.279 ;
     RECT  2.376 14.279 22.23 14.549 ;
     RECT  2.376 14.549 22.194 15.989 ;
     RECT  2.376 15.989 22.158 17.069 ;
     RECT  2.376 17.069 21.978 17.609 ;
     RECT  2.415 17.609 21.978 19.373 ;
     RECT  2.415 19.373 21.798 19.499 ;
     RECT  2.415 19.499 21.726 20.075 ;
     RECT  22.464 20.731 22.482 20.849 ;
     RECT  2.415 20.075 21.597 21.001 ;
     RECT  2.415 21.001 21.618 21.119 ;
     RECT  2.415 21.119 21.597 22.427 ;
     RECT  2.415 22.427 21.405 22.469 ;
     RECT  5.115 22.469 21.405 22.541 ;
     RECT  5.115 22.541 17.802 22.577 ;
     RECT  2.415 22.469 4.338 22.697 ;
     RECT  5.115 22.577 5.742 22.697 ;
     RECT  6.48 22.577 17.802 22.697 ;
     RECT  18.576 22.541 21.405 22.697 ;
     RECT  8.388 22.697 17.802 22.739 ;
     RECT  2.952 22.697 4.338 22.781 ;
     RECT  8.568 22.739 15.102 22.781 ;
     RECT  12.384 22.781 14.202 22.811 ;
     RECT  8.568 22.781 10.746 22.829 ;
     RECT  12.384 22.811 13.41 22.829 ;
     RECT  8.568 22.829 9.558 22.877 ;
     RECT  13.176 22.829 13.194 22.877 ;
     RECT  6.48 22.697 7.398 23.069 ;
     RECT  6.48 23.069 6.75 23.117 ;
     RECT  18.576 22.697 20.898 23.117 ;
     RECT  18.576 23.117 20.358 23.213 ;
     RECT  3.276 22.781 4.338 23.405 ;
     RECT  9.288 22.877 9.558 23.405 ;
     RECT  14.184 22.811 14.202 23.405 ;
     RECT  3.42 23.405 4.338 23.453 ;
     RECT  3.996 23.453 4.338 23.645 ;
     RECT  20.34 23.213 20.358 23.645 ;
     RECT  6.732 23.117 6.75 23.693 ;
     RECT  18.576 23.213 19.53 23.693 ;
     RECT  5.724 22.697 5.742 23.741 ;
     RECT  18.576 23.693 18.594 23.741 ;
     RECT  19.512 23.693 19.53 23.789 ;
     RECT  16.236 22.739 17.802 23.837 ;
     RECT  9.288 23.405 9.306 23.981 ;
     RECT  10.728 22.829 10.746 23.981 ;
     RECT  12.384 22.829 12.402 23.981 ;
     RECT  17.532 23.837 17.802 24.605 ;
     RECT  2.952 24.571 2.97 24.619 ;
     RECT  16.236 23.837 16.794 24.653 ;
     RECT  2.952 24.619 3.078 24.701 ;
     RECT  17.532 24.605 17.55 24.701 ;
     RECT  3.06 24.701 3.078 24.749 ;
     RECT  11.124 24.619 11.142 24.749 ;
     RECT  15.084 22.781 15.102 24.749 ;
     RECT  4.32 23.645 4.338 24.797 ;
     RECT  9.252 24.667 9.27 24.797 ;
     RECT  12.852 24.667 12.87 24.797 ;
     RECT  16.776 24.653 16.794 24.797 ;
    LAYER M4 ;
     RECT  2.365 4.656 2.408 4.68 ;
     RECT  2.401 7.968 2.408 7.992 ;
     RECT  2.365 14.208 2.408 14.232 ;
     RECT  2.408 2.148 2.512 22.692 ;
     RECT  2.512 2.256 2.704 22.692 ;
     RECT  2.897 24.672 2.924 24.696 ;
     RECT  2.704 22.176 2.941 22.692 ;
     RECT  2.924 24.576 3.005 24.696 ;
     RECT  3.005 24.576 3.011 24.744 ;
     RECT  3.011 24.624 3.089 24.744 ;
     RECT  3.089 24.624 3.107 24.648 ;
     RECT  2.704 18.624 3.133 21.096 ;
     RECT  2.941 22.176 3.265 22.776 ;
     RECT  2.704 3.936 3.34 6.264 ;
     RECT  3.265 22.176 3.365 23.4 ;
     RECT  3.34 4.32 3.413 6.264 ;
     RECT  3.365 22.176 3.413 23.448 ;
     RECT  2.704 2.256 3.443 2.904 ;
     RECT  3.413 23.28 3.491 23.448 ;
     RECT  3.491 23.376 3.539 23.448 ;
     RECT  3.413 5.472 3.685 6.264 ;
     RECT  3.133 20.592 3.701 21.096 ;
     RECT  2.704 7.968 3.731 9.144 ;
     RECT  3.133 18.624 3.769 19.368 ;
     RECT  3.443 2.256 3.773 2.28 ;
     RECT  3.701 21.072 3.841 21.096 ;
     RECT  3.413 22.176 3.841 22.2 ;
     RECT  3.685 5.472 3.949 6.84 ;
     RECT  3.913 7.92 3.949 7.944 ;
     RECT  2.704 10.704 3.973 10.728 ;
     RECT  3.769 17.184 3.985 19.368 ;
     RECT  2.704 12.72 4.021 12.744 ;
     RECT  2.704 13.92 4.021 15.192 ;
     RECT  3.731 9.12 4.025 9.144 ;
     RECT  4.021 12.72 4.237 15.192 ;
     RECT  3.413 4.32 4.453 4.392 ;
     RECT  3.949 5.472 4.453 7.944 ;
     RECT  3.985 16.512 4.453 19.368 ;
     RECT  4.237 12.72 4.501 15.336 ;
     RECT  4.453 16.512 4.501 19.56 ;
     RECT  4.453 3.408 4.597 7.944 ;
     RECT  4.597 3.312 4.741 7.944 ;
     RECT  3.973 10.704 4.741 11.64 ;
     RECT  4.501 12.72 4.741 19.56 ;
     RECT  4.741 10.704 4.885 19.56 ;
     RECT  4.885 10.704 5.065 19.656 ;
     RECT  4.741 2.88 5.108 7.944 ;
     RECT  4.885 9.696 5.108 9.72 ;
     RECT  5.065 10.704 5.108 19.896 ;
     RECT  3.841 21.072 5.108 22.2 ;
     RECT  3.985 23.616 5.108 23.64 ;
     RECT  5.108 2.148 5.212 23.64 ;
     RECT  5.212 2.418 5.404 22.422 ;
     RECT  5.404 10.224 5.645 21.144 ;
     RECT  5.645 18.24 5.699 21.144 ;
     RECT  5.212 23.616 5.713 23.64 ;
     RECT  5.404 2.592 5.789 8.088 ;
     RECT  5.645 10.224 5.891 17.256 ;
     RECT  5.789 2.592 5.932 7.368 ;
     RECT  5.891 10.224 5.987 11.544 ;
     RECT  5.891 12.864 6.149 17.256 ;
     RECT  6.149 12.864 6.257 17.064 ;
     RECT  5.713 23.616 6.469 23.736 ;
     RECT  5.932 2.592 6.505 4.584 ;
     RECT  5.699 19.104 6.659 21.144 ;
     RECT  6.505 2.448 7.045 4.584 ;
     RECT  5.932 5.712 7.045 7.368 ;
     RECT  5.404 9.072 7.052 9.096 ;
     RECT  7.052 8.496 7.081 9.096 ;
     RECT  6.659 20.784 7.153 21.144 ;
     RECT  5.987 10.224 7.189 10.248 ;
     RECT  7.081 8.496 7.225 9.144 ;
     RECT  7.189 10.224 7.225 10.392 ;
     RECT  6.257 14.208 7.369 17.064 ;
     RECT  7.009 18.24 7.369 18.264 ;
     RECT  6.469 23.088 7.369 23.736 ;
     RECT  7.045 2.448 7.429 7.368 ;
     RECT  6.659 19.296 7.657 19.656 ;
     RECT  7.153 20.784 7.657 22.056 ;
     RECT  7.429 2.448 7.808 7.416 ;
     RECT  7.225 8.496 7.808 10.392 ;
     RECT  5.987 11.376 7.808 11.544 ;
     RECT  6.257 12.864 7.808 13.128 ;
     RECT  7.369 14.208 7.808 18.264 ;
     RECT  7.657 19.296 7.808 22.056 ;
     RECT  7.369 23.04 7.808 23.736 ;
     RECT  7.808 2.148 7.912 23.736 ;
     RECT  7.912 2.418 8.104 23.736 ;
     RECT  8.104 11.424 8.417 16.056 ;
     RECT  8.104 8.448 8.597 9.864 ;
     RECT  8.417 11.424 8.705 14.808 ;
     RECT  8.104 17.664 8.813 23.736 ;
     RECT  8.104 2.784 9.097 7.464 ;
     RECT  8.597 8.448 9.097 9.336 ;
     RECT  8.417 15.984 9.097 16.056 ;
     RECT  8.813 17.904 9.241 23.736 ;
     RECT  4.309 24.768 9.241 24.792 ;
     RECT  9.097 2.784 9.245 9.336 ;
     RECT  9.241 17.904 9.281 24.792 ;
     RECT  9.281 17.904 9.353 24.696 ;
     RECT  9.097 15.984 9.565 16.584 ;
     RECT  9.565 15.984 9.637 16.632 ;
     RECT  8.705 11.424 9.925 14.52 ;
     RECT  9.637 15.984 9.925 16.824 ;
     RECT  9.925 10.608 9.997 14.52 ;
     RECT  9.925 15.696 9.997 16.824 ;
     RECT  9.245 2.784 10.357 9.288 ;
     RECT  10.357 2.784 10.465 9.384 ;
     RECT  9.997 10.608 10.465 16.824 ;
     RECT  10.465 2.784 10.508 16.824 ;
     RECT  9.353 17.904 10.508 21.144 ;
     RECT  9.353 22.176 10.508 24.696 ;
     RECT  10.508 2.148 10.612 24.696 ;
     RECT  10.612 2.256 10.804 24.696 ;
     RECT  10.804 10.608 10.865 16.872 ;
     RECT  10.804 17.904 10.973 18.264 ;
     RECT  10.804 22.176 11.074 24.696 ;
     RECT  10.804 19.296 11.081 20.328 ;
     RECT  10.804 2.256 11.153 9.384 ;
     RECT  11.074 22.176 11.219 24.744 ;
     RECT  11.219 24.624 11.363 24.744 ;
     RECT  11.363 24.672 11.411 24.744 ;
     RECT  10.973 17.904 11.477 17.928 ;
     RECT  11.153 2.256 11.549 2.76 ;
     RECT  10.865 10.608 11.833 15.48 ;
     RECT  10.865 16.608 11.833 16.872 ;
     RECT  11.081 19.296 11.905 20.136 ;
     RECT  11.833 10.608 11.981 16.872 ;
     RECT  11.153 3.84 12.013 9.384 ;
     RECT  11.981 16.848 12.013 16.872 ;
     RECT  12.013 16.848 12.125 17.688 ;
     RECT  11.219 22.176 12.229 23.064 ;
     RECT  12.121 2.832 12.277 2.856 ;
     RECT  12.013 3.84 12.277 9.624 ;
     RECT  12.229 21.552 12.373 23.064 ;
     RECT  11.411 24.672 12.373 24.696 ;
     RECT  12.373 21.552 12.517 24.696 ;
     RECT  12.277 2.832 12.757 9.624 ;
     RECT  11.981 10.608 12.757 15.48 ;
     RECT  11.905 19.248 12.757 20.136 ;
     RECT  12.517 21.552 12.841 24.744 ;
     RECT  12.757 2.832 12.985 15.48 ;
     RECT  13.093 1.152 13.129 1.176 ;
     RECT  12.985 2.448 13.129 15.48 ;
     RECT  13.129 1.152 13.165 15.48 ;
     RECT  13.165 0.576 13.208 15.48 ;
     RECT  12.125 17.664 13.208 17.688 ;
     RECT  12.757 19.152 13.208 20.232 ;
     RECT  12.841 21.552 13.208 24.792 ;
     RECT  13.208 0.576 13.504 24.792 ;
     RECT  13.504 0.576 13.561 17.688 ;
     RECT  13.561 0.096 13.637 17.688 ;
     RECT  13.637 0.096 13.753 17.64 ;
     RECT  13.753 1.728 13.853 17.64 ;
     RECT  13.853 1.728 14.069 17.064 ;
     RECT  14.069 15.888 14.821 17.064 ;
     RECT  14.821 15.888 14.915 17.688 ;
     RECT  13.753 0.096 14.929 0.6 ;
     RECT  14.069 1.728 14.929 14.664 ;
     RECT  14.915 16.752 15.212 17.688 ;
     RECT  14.929 0.096 15.405 14.664 ;
     RECT  15.405 0.096 15.443 14.76 ;
     RECT  15.443 1.728 15.505 14.76 ;
     RECT  15.443 0.096 15.635 0.504 ;
     RECT  15.635 0.096 15.827 0.408 ;
     RECT  15.505 1.728 15.908 15.432 ;
     RECT  15.212 16.752 15.908 18.168 ;
     RECT  13.504 19.392 15.908 24.792 ;
     RECT  15.827 0.096 15.977 0.36 ;
     RECT  15.908 1.728 16.204 24.792 ;
     RECT  15.977 0.144 16.451 0.36 ;
     RECT  16.204 1.728 16.499 15.432 ;
     RECT  16.499 1.728 16.553 1.896 ;
     RECT  16.499 2.88 16.625 15.432 ;
     RECT  16.451 0.144 16.661 0.312 ;
     RECT  16.625 3.408 16.697 15.432 ;
     RECT  16.204 23.088 16.805 24.792 ;
     RECT  16.661 0.144 16.913 0.168 ;
     RECT  16.553 1.776 16.913 1.896 ;
     RECT  16.913 1.872 17.201 1.896 ;
     RECT  16.204 19.296 17.221 19.464 ;
     RECT  16.204 20.592 17.221 22.056 ;
     RECT  17.221 19.296 17.308 22.056 ;
     RECT  17.308 19.296 17.413 19.56 ;
     RECT  17.413 19.008 17.449 19.56 ;
     RECT  17.449 18.72 17.555 19.56 ;
     RECT  16.805 23.088 17.561 24.696 ;
     RECT  16.697 3.408 17.605 14.28 ;
     RECT  17.561 23.088 17.813 24.6 ;
     RECT  17.605 2.784 17.881 14.28 ;
     RECT  16.697 15.408 17.881 15.432 ;
     RECT  17.485 17.088 18.092 17.112 ;
     RECT  17.881 2.784 18.608 15.432 ;
     RECT  18.092 16.512 18.608 17.112 ;
     RECT  17.555 18.816 18.608 19.56 ;
     RECT  17.308 20.592 18.608 22.056 ;
     RECT  17.813 23.088 18.608 23.784 ;
     RECT  18.608 2.148 18.712 23.784 ;
     RECT  18.712 2.418 18.904 23.784 ;
     RECT  18.904 5.856 19.189 16.008 ;
     RECT  18.904 2.832 19.427 3.432 ;
     RECT  18.904 17.088 19.523 18.408 ;
     RECT  18.904 23.088 19.541 23.784 ;
     RECT  18.904 19.392 19.721 22.056 ;
     RECT  19.189 14.448 19.757 16.008 ;
     RECT  19.427 2.832 19.916 3.192 ;
     RECT  19.721 19.392 19.933 21.576 ;
     RECT  19.916 2.256 20.003 3.192 ;
     RECT  18.904 4.704 20.149 4.728 ;
     RECT  19.189 5.856 20.149 13.32 ;
     RECT  20.149 4.704 20.213 13.32 ;
     RECT  19.541 23.088 20.369 23.64 ;
     RECT  19.757 15.12 20.545 16.008 ;
     RECT  19.523 17.088 20.545 17.64 ;
     RECT  20.213 4.704 20.725 14.136 ;
     RECT  20.545 15.12 20.725 17.64 ;
     RECT  20.725 4.704 20.78 17.64 ;
     RECT  20.369 23.088 20.909 23.112 ;
     RECT  19.933 18.816 21.013 21.576 ;
     RECT  20.003 2.832 21.301 3.192 ;
     RECT  20.78 4.512 21.301 17.64 ;
     RECT  21.301 2.832 21.308 17.64 ;
     RECT  21.013 18.816 21.308 22.692 ;
     RECT  21.308 2.148 21.412 22.692 ;
     RECT  21.412 2.418 21.604 22.422 ;
     RECT  21.604 4.128 21.701 5.496 ;
     RECT  21.604 6.864 21.701 10.68 ;
     RECT  21.701 6.864 21.731 9.912 ;
     RECT  21.731 6.864 21.773 9.864 ;
     RECT  21.701 5.472 21.809 5.496 ;
     RECT  21.604 13.344 21.845 13.368 ;
     RECT  21.773 6.864 21.881 9.816 ;
     RECT  21.604 17.616 21.953 17.64 ;
     RECT  21.604 11.664 22.061 11.928 ;
     RECT  21.701 4.128 22.133 4.152 ;
     RECT  21.881 6.864 22.205 9.048 ;
     RECT  22.205 7.632 22.277 9.048 ;
     RECT  22.277 8.496 22.421 9.048 ;
     RECT  22.777 12.624 23.245 12.648 ;
     RECT  23.245 12.624 24.756 12.648 ;
     RECT  23.245 12.648 24.78 12.72 ;
     RECT  23.245 12.72 24.756 12.744 ;
     RECT  23.245 12.744 24.78 12.816 ;
     RECT  23.245 12.816 24.756 12.84 ;
     RECT  23.245 12.84 24.78 12.912 ;
     RECT  23.245 12.912 24.756 12.936 ;
    LAYER M5 ;
     RECT  13.032 0.016 13.104 0.084 ;
     RECT  13.128 0.016 13.2 0.084 ;
     RECT  13.224 0.016 13.296 0.084 ;
     RECT  13.32 0.016 13.392 0.084 ;
     RECT  13.416 0.016 13.488 0.084 ;
     RECT  13.512 0.016 13.584 0.084 ;
     RECT  13.608 0.016 13.68 0.084 ;
     RECT  13.704 0.016 13.776 0.084 ;
     RECT  13.8 0.016 13.872 0.084 ;
     RECT  13.896 0.016 13.968 0.084 ;
     RECT  13.992 0.016 14.064 0.084 ;
     RECT  14.088 0.016 14.16 0.084 ;
     RECT  14.184 0.016 14.256 0.084 ;
     RECT  14.28 0.016 14.352 0.084 ;
     RECT  14.376 0.016 14.448 0.084 ;
     RECT  14.472 0.016 14.544 0.084 ;
     RECT  14.568 0.016 14.64 0.084 ;
     RECT  14.664 0.016 14.736 0.084 ;
     RECT  14.76 0.016 14.832 0.084 ;
     RECT  14.856 0.016 14.928 0.084 ;
     RECT  14.952 0.016 15.024 0.084 ;
     RECT  15.048 0.016 15.12 0.084 ;
     RECT  15.144 0.016 15.216 0.084 ;
     RECT  15.24 0.016 15.312 0.084 ;
     RECT  15.336 0.016 15.408 0.084 ;
     RECT  15.432 0.016 15.504 0.084 ;
     RECT  15.528 0.016 15.6 0.084 ;
     RECT  15.624 0.016 15.696 0.084 ;
     RECT  15.72 0.016 15.792 0.084 ;
     RECT  15.816 0.016 15.888 0.084 ;
     RECT  15.912 0.016 15.984 0.084 ;
     RECT  13.008 0.084 16.008 0.325 ;
     RECT  13.008 0.325 16.44 1.763 ;
     RECT  2.4 2.137 2.52 2.151 ;
     RECT  5.1 2.137 5.22 2.151 ;
     RECT  7.8 2.137 7.92 2.151 ;
     RECT  10.5 2.137 10.62 2.151 ;
     RECT  18.6 2.137 18.72 2.151 ;
     RECT  21.3 2.137 21.42 2.151 ;
     RECT  2.4 2.151 2.712 2.245 ;
     RECT  10.5 2.151 10.812 2.245 ;
     RECT  13.008 1.763 14.088 2.291 ;
     RECT  15.6 1.763 16.44 2.485 ;
     RECT  7.8 2.151 8.112 2.773 ;
     RECT  18.6 2.151 18.912 2.773 ;
     RECT  10.5 2.245 11.448 2.821 ;
     RECT  17.616 2.773 18.912 2.821 ;
     RECT  19.968 2.245 19.992 2.821 ;
     RECT  2.4 2.245 3.432 2.915 ;
     RECT  17.616 2.821 19.992 3.203 ;
     RECT  6.816 2.773 8.112 3.205 ;
     RECT  5.1 2.151 5.412 3.301 ;
     RECT  4.608 3.301 5.412 3.397 ;
     RECT  13.008 2.291 13.512 3.397 ;
     RECT  6.816 3.205 9.096 3.443 ;
     RECT  17.616 3.203 19.416 3.443 ;
     RECT  4.464 3.397 5.412 3.685 ;
     RECT  10.272 2.821 11.448 3.685 ;
     RECT  13.008 3.397 13.656 3.685 ;
     RECT  4.464 3.685 5.784 3.781 ;
     RECT  2.4 2.915 2.712 3.925 ;
     RECT  4.464 3.781 5.832 4.117 ;
     RECT  2.4 3.925 3.288 4.309 ;
     RECT  4.464 4.117 5.88 4.309 ;
     RECT  10.272 3.685 13.656 4.501 ;
     RECT  21.3 2.151 21.612 4.501 ;
     RECT  2.4 4.309 5.88 4.691 ;
     RECT  6.864 3.443 9.096 4.741 ;
     RECT  10.272 4.501 13.704 4.741 ;
     RECT  15.6 2.485 16.488 4.789 ;
     RECT  17.664 3.443 18.912 4.789 ;
     RECT  6.864 4.741 13.704 5.029 ;
     RECT  20.832 4.501 21.612 5.605 ;
     RECT  6.864 5.029 14.52 5.653 ;
     RECT  15.6 4.789 18.912 5.653 ;
     RECT  3.696 4.691 5.88 5.699 ;
     RECT  6.864 5.653 18.912 5.843 ;
     RECT  20.16 5.605 21.612 5.845 ;
     RECT  7.8 5.843 18.912 6.037 ;
     RECT  19.92 5.845 21.612 6.037 ;
     RECT  4.464 5.699 5.88 6.371 ;
     RECT  7.8 6.037 21.612 6.707 ;
     RECT  4.464 6.371 5.832 6.709 ;
     RECT  3.696 6.709 5.832 6.851 ;
     RECT  9.168 6.707 21.612 6.995 ;
     RECT  7.8 6.707 8.112 7.093 ;
     RECT  9.552 6.995 21.612 7.667 ;
     RECT  9.552 7.667 11.4 7.955 ;
     RECT  9.792 7.955 11.4 8.003 ;
     RECT  7.2 7.093 8.112 8.485 ;
     RECT  3.696 6.851 3.72 8.579 ;
     RECT  12.624 7.667 21.612 9.013 ;
     RECT  7.104 8.485 8.112 9.107 ;
     RECT  9.792 8.003 10.812 9.107 ;
     RECT  4.896 6.851 5.832 9.731 ;
     RECT  12.048 9.013 21.612 9.877 ;
     RECT  4.944 9.731 5.832 10.213 ;
     RECT  12.048 9.877 21.72 10.643 ;
     RECT  4.944 10.213 5.976 10.693 ;
     RECT  3.984 10.693 5.976 10.883 ;
     RECT  9.888 9.107 10.812 11.459 ;
     RECT  12.816 10.643 21.72 11.507 ;
     RECT  3.984 10.883 5.832 11.651 ;
     RECT  12.864 11.507 21.72 11.699 ;
     RECT  4.416 11.651 5.832 12.373 ;
     RECT  4.416 12.373 5.88 13.045 ;
     RECT  7.2 9.107 8.112 13.573 ;
     RECT  4.368 13.045 5.88 13.763 ;
     RECT  2.4 4.691 2.712 13.909 ;
     RECT  2.4 13.909 3.144 14.149 ;
     RECT  4.368 13.763 5.832 14.149 ;
     RECT  12.864 11.699 21.612 14.531 ;
     RECT  12.864 14.531 13.512 14.867 ;
     RECT  11.952 15.109 11.976 15.251 ;
     RECT  7.2 13.573 8.808 16.453 ;
     RECT  9.936 11.459 10.812 16.549 ;
     RECT  6.816 16.453 8.808 17.075 ;
     RECT  2.4 14.149 5.832 17.219 ;
     RECT  9.84 16.549 10.812 18.323 ;
     RECT  2.4 17.219 3.48 18.661 ;
     RECT  4.512 17.219 5.832 18.661 ;
     RECT  2.4 18.661 5.832 19.093 ;
     RECT  13.2 14.867 13.512 19.141 ;
     RECT  10.368 18.323 10.812 19.331 ;
     RECT  14.736 14.531 21.612 19.427 ;
     RECT  14.736 19.427 19.176 19.475 ;
     RECT  17.232 19.475 19.176 19.571 ;
     RECT  2.4 19.093 6.648 20.003 ;
     RECT  18.6 19.571 19.176 20.581 ;
     RECT  14.736 19.475 16.212 20.627 ;
     RECT  18.6 20.581 19.368 20.725 ;
     RECT  20.64 19.427 21.612 20.725 ;
     RECT  6.624 20.003 6.648 20.819 ;
     RECT  18.6 20.725 21.612 20.867 ;
     RECT  17.232 19.571 17.256 21.155 ;
     RECT  18.6 20.867 20.04 21.155 ;
     RECT  2.4 20.003 5.412 21.395 ;
     RECT  20.016 21.155 20.04 21.587 ;
     RECT  12.768 19.141 13.512 22.069 ;
     RECT  14.736 20.627 14.76 22.069 ;
     RECT  10.5 19.331 10.812 22.165 ;
     RECT  12.768 22.069 14.76 22.165 ;
     RECT  7.8 17.075 8.808 22.213 ;
     RECT  10.368 22.165 10.812 22.213 ;
     RECT  11.856 22.165 14.76 22.213 ;
     RECT  21.024 20.867 21.612 22.259 ;
     RECT  5.1 21.395 5.412 22.689 ;
     RECT  15.9 20.627 16.212 22.689 ;
     RECT  18.6 21.155 18.912 22.689 ;
     RECT  21.3 22.259 21.612 22.689 ;
     RECT  2.4 21.395 3.48 22.703 ;
     RECT  5.1 22.689 5.22 22.703 ;
     RECT  7.8 22.213 14.76 22.703 ;
     RECT  15.9 22.689 16.02 22.703 ;
     RECT  18.6 22.689 18.72 22.703 ;
     RECT  21.3 22.689 21.42 22.703 ;
     RECT  8.784 22.703 14.76 23.029 ;
     RECT  2.976 22.703 3.48 23.365 ;
     RECT  2.976 23.365 3.528 24.661 ;
     RECT  2.928 24.661 3.528 24.756 ;
     RECT  2.952 24.756 3.024 24.784 ;
     RECT  3.048 24.756 3.12 24.784 ;
     RECT  3.144 24.756 3.216 24.784 ;
     RECT  3.24 24.756 3.312 24.784 ;
     RECT  3.336 24.756 3.408 24.784 ;
     RECT  3.432 24.756 3.504 24.784 ;
     RECT  8.784 23.029 14.856 24.756 ;
     RECT  8.808 24.756 8.88 24.784 ;
     RECT  8.904 24.756 8.976 24.784 ;
     RECT  9 24.756 9.072 24.784 ;
     RECT  9.096 24.756 9.168 24.784 ;
     RECT  9.192 24.756 9.264 24.784 ;
     RECT  9.288 24.756 9.36 24.784 ;
     RECT  9.384 24.756 9.456 24.784 ;
     RECT  9.48 24.756 9.552 24.784 ;
     RECT  9.576 24.756 9.648 24.784 ;
     RECT  9.672 24.756 9.744 24.784 ;
     RECT  9.768 24.756 9.84 24.784 ;
     RECT  9.864 24.756 9.936 24.784 ;
     RECT  9.96 24.756 10.032 24.784 ;
     RECT  10.056 24.756 10.128 24.784 ;
     RECT  10.152 24.756 10.224 24.784 ;
     RECT  10.248 24.756 10.32 24.784 ;
     RECT  10.344 24.756 10.416 24.784 ;
     RECT  10.44 24.756 10.512 24.784 ;
     RECT  10.536 24.756 10.608 24.784 ;
     RECT  10.632 24.756 10.704 24.784 ;
     RECT  10.728 24.756 10.8 24.784 ;
     RECT  10.824 24.756 10.896 24.784 ;
     RECT  10.92 24.756 10.992 24.784 ;
     RECT  11.016 24.756 11.088 24.784 ;
     RECT  11.112 24.756 11.184 24.784 ;
     RECT  11.208 24.756 11.28 24.784 ;
     RECT  11.304 24.756 11.376 24.784 ;
     RECT  11.4 24.756 11.472 24.784 ;
     RECT  11.496 24.756 11.568 24.784 ;
     RECT  11.592 24.756 11.664 24.784 ;
     RECT  11.688 24.756 11.76 24.784 ;
     RECT  11.784 24.756 11.856 24.784 ;
     RECT  11.88 24.756 11.952 24.784 ;
     RECT  11.976 24.756 12.048 24.784 ;
     RECT  12.072 24.756 12.144 24.784 ;
     RECT  12.168 24.756 12.24 24.784 ;
     RECT  12.264 24.756 12.336 24.784 ;
     RECT  12.36 24.756 12.432 24.784 ;
     RECT  12.456 24.756 12.528 24.784 ;
     RECT  12.552 24.756 12.624 24.784 ;
     RECT  12.648 24.756 12.72 24.784 ;
     RECT  12.744 24.756 12.816 24.784 ;
     RECT  12.84 24.756 12.912 24.784 ;
     RECT  12.936 24.756 13.008 24.784 ;
     RECT  13.032 24.756 13.104 24.784 ;
     RECT  13.128 24.756 13.2 24.784 ;
     RECT  13.224 24.756 13.296 24.784 ;
     RECT  13.32 24.756 13.392 24.784 ;
     RECT  13.416 24.756 13.488 24.784 ;
     RECT  13.512 24.756 13.584 24.784 ;
     RECT  13.608 24.756 13.68 24.784 ;
     RECT  13.704 24.756 13.776 24.784 ;
     RECT  13.8 24.756 13.872 24.784 ;
     RECT  13.896 24.756 13.968 24.784 ;
     RECT  13.992 24.756 14.064 24.784 ;
     RECT  14.088 24.756 14.16 24.784 ;
     RECT  14.184 24.756 14.256 24.784 ;
     RECT  14.28 24.756 14.352 24.784 ;
     RECT  14.376 24.756 14.448 24.784 ;
     RECT  14.472 24.756 14.544 24.784 ;
     RECT  14.568 24.756 14.64 24.784 ;
     RECT  14.664 24.756 14.736 24.784 ;
     RECT  14.76 24.756 14.832 24.784 ;
     RECT  14.088 1.763 15.6 2.291 ;
     RECT  18.912 2.245 19.968 2.821 ;
     RECT  19.992 2.245 21.3 3.203 ;
     RECT  13.512 2.291 13.656 3.397 ;
     RECT  5.412 2.773 6.816 3.443 ;
     RECT  16.488 2.773 17.616 3.443 ;
     RECT  2.712 2.915 3.432 3.301 ;
     RECT  19.416 3.203 21.3 3.443 ;
     RECT  9.096 3.205 10.272 4.741 ;
     RECT  2.712 3.301 4.608 3.397 ;
     RECT  2.712 3.397 4.464 3.925 ;
     RECT  5.412 3.443 6.864 3.685 ;
     RECT  16.488 3.443 17.664 4.789 ;
     RECT  20.832 3.443 21.3 4.501 ;
     RECT  5.784 3.685 6.864 3.781 ;
     RECT  5.832 3.781 6.864 4.117 ;
     RECT  3.288 3.925 4.464 4.309 ;
     RECT  5.88 4.117 6.864 5.843 ;
     RECT  2.712 4.691 3.696 5.699 ;
     RECT  14.52 5.029 15.6 5.653 ;
     RECT  18.912 5.605 20.16 5.845 ;
     RECT  2.712 5.699 4.464 6.709 ;
     RECT  5.88 5.843 7.8 6.371 ;
     RECT  18.912 5.845 19.92 6.037 ;
     RECT  5.832 6.371 7.8 7.093 ;
     RECT  8.112 6.707 9.168 6.995 ;
     RECT  2.712 6.709 3.696 8.579 ;
     RECT  3.72 6.851 4.896 8.579 ;
     RECT  8.112 6.995 9.552 7.955 ;
     RECT  5.832 7.093 7.2 8.485 ;
     RECT  11.4 7.667 12.624 8.003 ;
     RECT  10.812 8.003 12.624 9.013 ;
     RECT  5.832 8.485 7.104 9.107 ;
     RECT  10.812 9.013 12.048 10.643 ;
     RECT  5.832 9.107 7.2 10.213 ;
     RECT  4.896 9.731 4.944 10.693 ;
     RECT  5.976 10.213 7.2 10.883 ;
     RECT  2.712 10.693 3.984 11.651 ;
     RECT  5.832 10.883 7.2 12.373 ;
     RECT  4.368 11.651 4.416 13.045 ;
     RECT  5.88 12.373 7.2 13.763 ;
     RECT  8.808 13.573 9.936 16.549 ;
     RECT  5.832 13.763 7.2 16.453 ;
     RECT  3.144 13.909 4.368 14.149 ;
     RECT  13.512 14.531 14.736 22.069 ;
     RECT  12.864 14.867 13.2 15.109 ;
     RECT  10.812 15.109 11.952 15.251 ;
     RECT  11.976 15.109 13.2 15.251 ;
     RECT  5.832 16.453 6.816 17.075 ;
     RECT  8.808 16.549 9.84 18.323 ;
     RECT  3.48 17.219 4.512 18.661 ;
     RECT  6.648 19.093 7.8 20.819 ;
     RECT  19.176 19.427 20.64 20.581 ;
     RECT  16.212 19.475 17.232 21.155 ;
     RECT  17.256 19.571 18.6 21.155 ;
     RECT  5.412 20.003 6.624 20.819 ;
     RECT  19.368 20.581 20.64 20.725 ;
     RECT  14.76 20.627 15.9 22.703 ;
     RECT  20.04 20.867 21.024 21.587 ;
     RECT  18.912 21.155 20.016 21.587 ;
     RECT  10.812 22.165 11.856 22.213 ;
     RECT  14.76 22.703 14.856 23.029 ;
  END
END dsfd_dvland_70
END LIBRARY
